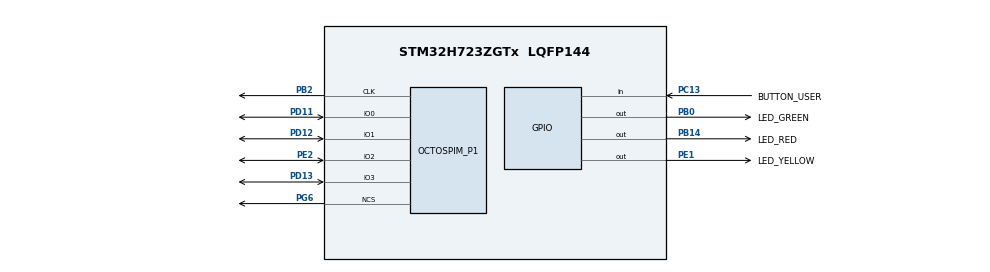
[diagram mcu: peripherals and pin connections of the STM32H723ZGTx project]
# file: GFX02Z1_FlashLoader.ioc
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Mcu.Family=STM32H7
Mcu.Name=STM32H723ZGTx
Mcu.Package=LQFP144
NVIC.PriorityGroup=NVIC_PRIORITYGROUP_4
OCTOSPI1.ChipSelectHighTime=2
OCTOSPI1.ClockPrescaler=2
OCTOSPI1.DeviceSize=23
OCTOSPI1.FifoThreshold=4
OCTOSPI1.MemoryType=HAL_OSPI_MEMTYPE_MACRONIX
OCTOSPI1.SampleShifting=HAL_OSPI_SAMPLE_SHIFTING_HALFCYCLE
PB0.GPIO_Label=LED_GREEN
PB0.GPIO_Speed=GPIO_SPEED_FREQ_MEDIUM
PB0.PinState=GPIO_PIN_RESET
PB0.Signal=GPIO_Output
PB14.GPIO_Label=LED_RED
PB14.GPIO_Speed=GPIO_SPEED_FREQ_MEDIUM
PB14.Signal=GPIO_Output
PB2.Mode=O1_P1_CLK
PB2.Signal=OCTOSPIM_P1_CLK
PC13.GPIO_Label=BUTTON_USER
PC13.Signal=GPIO_Input
PC14-OSC32_IN.Mode=LSE-External-Oscillator
PC14-OSC32_IN.Signal=RCC_OSC32_IN
PC15-OSC32_OUT.Mode=LSE-External-Oscillator
PC15-OSC32_OUT.Signal=RCC_OSC32_OUT
PD11.Mode=OCTOSPI1_IOL_Port1L
PD11.Signal=OCTOSPIM_P1_IO0
PD12.Mode=OCTOSPI1_IOL_Port1L
PD12.Signal=OCTOSPIM_P1_IO1
PD13.Mode=OCTOSPI1_IOL_Port1L
PD13.Signal=OCTOSPIM_P1_IO3
PE1.GPIO_Label=LED_YELLOW
PE1.GPIO_Speed=GPIO_SPEED_FREQ_MEDIUM
PE1.Signal=GPIO_Output
PE2.Mode=OCTOSPI1_IOL_Port1L
PE2.Signal=OCTOSPIM_P1_IO2
PG6.Mode=OCTOSPI1_Port1_NCS
PG6.Signal=OCTOSPIM_P1_NCS
PH0-OSC_IN.Mode=HSE-External-Clock-Source
PH0-OSC_IN.Signal=RCC_OSC_IN
ProjectManager.HeapSize=0x400
ProjectManager.StackSize=0x400
ProjectManager.TargetToolchain=STM32CubeIDE
RCC.ADCFreq_Value=160000000
RCC.APB1Freq_Value=137500000
RCC.APB2Freq_Value=137500000
RCC.APB3Freq_Value=137500000
RCC.APB4Freq_Value=137500000
RCC.CortexFreq_Value=550000000
RCC.D1PPRE=RCC_APB3_DIV2
RCC.D2PPRE1=RCC_APB1_DIV2
RCC.D2PPRE2=RCC_APB2_DIV2
RCC.D3PPRE=RCC_APB4_DIV2
RCC.DIVM1=4
RCC.DIVM2=8
RCC.DIVN1=275
RCC.DIVN2=320
RCC.DIVP1=1
RCC.DIVQ1=4
RCC.FMCCLockSelection=RCC_FMCCLKSOURCE_PLL2
RCC.HCLKFreq_Value=275000000
RCC.HPRE=RCC_HCLK_DIV2
RCC.HSE_VALUE=8000000
RCC.PLLFRACN=0
RCC.PLLSourceVirtual=RCC_PLLSOURCE_HSE
RCC.QSPICLockSelection=RCC_OSPICLKSOURCE_PLL2
RCC.SYSCLKFreq_VALUE=550000000
RCC.SYSCLKSource=RCC_SYSCLKSOURCE_PLLCLK
RCC.USBCLockSelection=RCC_USBCLKSOURCE_HSI48
RCC.USBFreq_Value=48000000
STMicroelectronics.X-CUBE-DISPLAY.3.0.0.ApplicationCcDeviceJjApplication=GFX02Z1IiHelloWorld
STMicroelectronics.X-CUBE-DISPLAY.3.0.0.BoardOoPartJjLCDJjST7789V=FMC
STMicroelectronics.X-CUBE-DISPLAY.3.0.0.BoardOoPartJjMemoryJjMX25L6433F=OSPI
STMicroelectronics.X-CUBE-DISPLAY.3.0.0.DISPLAYCcBoardOoPartJjMemoryJjMX25L6433F=OSPI
STMicroelectronics.X-CUBE-DISPLAY.3.0.0.p_display_cache_lines=32
STMicroelectronics.X-CUBE-DISPLAY.3.0.0.p_display_te_event_source=TE_SRC_LCD
STMicroelectronics.X-CUBE-DISPLAY.3.0.0.p_display_te_use_hw_timer=false
STMicroelectronics.X-CUBE-DISPLAY.3.0.0.p_fmc_dma_tx_id=1\:0
STMicroelectronics.X-CUBE-DISPLAY.3.0.0.p_memory_dummy_cycle_read=8
STMicroelectronics.X-CUBE-DISPLAY.3.0.0.p_memory_dummy_cycle_read_dual=4
STMicroelectronics.X-CUBE-DISPLAY.3.0.0.p_memory_dummy_cycle_read_quad=6
STMicroelectronics.X-CUBE-DISPLAY.3.0.0.p_xspi_dma_instance_name=MDMA_Channel0
STMicroelectronics.X-CUBE-DISPLAY.3.0.0.p_xspi_mm_mode=false
STMicroelectronics.X-CUBE-DISPLAY.3.0.0_IsPackSelfContextualization=true
VP_OCTOSPI1_VS_quad.Mode=quad_mode
VP_STMicroelectronics.X-CUBE-DISPLAY_VS_BoardOoPartJjDISPLAY_3.0.0_3.0.0.Mode=BoardOoPartJjDISPLAY
board=NUCLEO-H723ZG

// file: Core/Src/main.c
/* USER CODE BEGIN Header */
/**
  ******************************************************************************
  * @file           : main.c
  * @brief          : Main program body
  ******************************************************************************
  * @attention
  *
  * Copyright (c) 2022 STMicroelectronics.
  * All rights reserved.
  *
  * This software is licensed under terms that can be found in the LICENSE file
  * in the root directory of this software component.
  * If no LICENSE file comes with this software, it is provided AS-IS.
  *
  ******************************************************************************
  */
/* USER CODE END Header */
#include "main.h"
#include "stm32h7xx_.h"

void SystemClock_Config(void);

extern void sFLASH_Init(void);
extern void sFLASH_WriteEnable(void);
extern uint8_t sFLASH_SendByte(uint8_t byte);

/**
  * @brief  The MX Initialization function.
  * @retval MX_Init
  */
void MX_Init(void)
{
  /* MCU Configuration--------------------------------------------------------*/

    /* Reset of all peripherals, Initializes the Flash interface and the Systick. */
  HAL_RCC_DeInit();
  HAL_DeInit();
  HAL_PWR_DeInit();

  /* Reset of all peripherals, Initializes the Flash interface and the Systick. */
  HAL_Init();

  /* Configure the system clock */
  SystemClock_Config();

  //初始化SPI配置及GPIO
  sFLASH_Init();

  //设置为32位地址模式
  /*!< Enable the write access to the FLASH */
  sFLASH_WriteEnable();
  sFLASH_SendByte(0x17);        //发送 BRWR (17h) 命令
  sFLASH_SendByte(0x80);        // 发送新的 Bank Address 值将BAR[7]设置为1
  FLASH_SPI_CS_HIGH();          // 拉高 CS 引脚，结束传输

}

void SystemClock_Config(void)
{
  RCC_OscInitTypeDef RCC_OscInitStruct = {0};
  RCC_ClkInitTypeDef RCC_ClkInitStruct = {0};

  /** Supply configuration update enable
  */
  HAL_PWREx_ConfigSupply(PWR_LDO_SUPPLY);

  /** Configure the main internal regulator output voltage
  */
  __HAL_PWR_VOLTAGESCALING_CONFIG(PWR_REGULATOR_VOLTAGE_SCALE0);

  while(!__HAL_PWR_GET_FLAG(PWR_FLAG_VOSRDY)) {}

  /** Macro to configure the PLL clock source
  */
  __HAL_RCC_PLL_PLLSOURCE_CONFIG(RCC_PLLSOURCE_HSE);
  /* Enable D2 domain SRAM3 Clock (0x30040000 AXI)*/
    __HAL_RCC_D2SRAM3_CLK_ENABLE();

  /** Initializes the RCC Oscillators according to the specified parameters
  * in the RCC_OscInitTypeDef structure.
  */
  RCC_OscInitStruct.OscillatorType = RCC_OSCILLATORTYPE_HSE;
  RCC_OscInitStruct.HSEState = RCC_HSE_ON;
  RCC_OscInitStruct.HSIState = RCC_HSI_OFF;
  RCC_OscInitStruct.CSIState = RCC_CSI_OFF;
  RCC_OscInitStruct.PLL.PLLState = RCC_PLL_ON;
  RCC_OscInitStruct.PLL.PLLSource = RCC_PLLSOURCE_HSE;
  RCC_OscInitStruct.PLL.PLLM = 5;
  RCC_OscInitStruct.PLL.PLLN = 160;
  RCC_OscInitStruct.PLL.PLLFRACN = 0;
  RCC_OscInitStruct.PLL.PLLP = 2;
  RCC_OscInitStruct.PLL.PLLQ = 2;
  RCC_OscInitStruct.PLL.PLLR = 8;
  RCC_OscInitStruct.PLL.PLLRGE = RCC_PLL1VCOWIDE;
  RCC_OscInitStruct.PLL.PLLVCOSEL = RCC_PLL1VCIRANGE_2;
  if (HAL_RCC_OscConfig(&RCC_OscInitStruct) != HAL_OK)
  {
    Error_Handler();
  }

  /** Initializes the CPU, AHB and APB buses clocks
  */
  RCC_ClkInitStruct.ClockType = RCC_CLOCKTYPE_HCLK|RCC_CLOCKTYPE_SYSCLK
                              |RCC_CLOCKTYPE_PCLK1|RCC_CLOCKTYPE_PCLK2
                              |RCC_CLOCKTYPE_D3PCLK1|RCC_CLOCKTYPE_D1PCLK1;
  RCC_ClkInitStruct.SYSCLKSource = RCC_SYSCLKSOURCE_PLLCLK;
  RCC_ClkInitStruct.SYSCLKDivider = RCC_SYSCLK_DIV1;
  RCC_ClkInitStruct.AHBCLKDivider = RCC_HCLK_DIV2;
  RCC_ClkInitStruct.APB3CLKDivider = RCC_APB3_DIV2;
  RCC_ClkInitStruct.APB1CLKDivider = RCC_HCLK_DIV4;
  RCC_ClkInitStruct.APB2CLKDivider = RCC_APB2_DIV2;
  RCC_ClkInitStruct.APB4CLKDivider = RCC_APB4_DIV2;

  if (HAL_RCC_ClockConfig(&RCC_ClkInitStruct, FLASH_LATENCY_5) != HAL_OK)
  {
    Error_Handler();
  }
}

void Error_Handler(void)
{
  /* USER CODE BEGIN Error_Handler_Debug */
  /* User can add his own implementation to report the HAL error return state */
  __disable_irq();

  while (1)
  {
  }

}
